# No Li and RDL/Metal 6 layer
# LEF technology file - generated from cadflow
# Creation date: Jul 5 2017
# 12-21-18 KKEL added OVERLAP layer; added EDGECAPACITANCE, 
#          CAPACITANCE CPERSQDIST, RESISTANCE RPERSQ,
#          DCCURRENTDENSITY AVERAGE, ACCURRENTDENSITY RMS 
#          for all relevant routing/cutlayers
# 04-01-19 KKEL removed off-grid offset value for METAL2
#          and simplified ACCURRENTDENSITY syntax to prevent 
#          RC Compiler parsing error

# Initilize top level parameters
VERSION 5.6 ;
BUSBITCHARS "[]" ;
DIVIDERCHAR "/" ;
UNITS
  TIME NANOSECONDS 1 ;
  CAPACITANCE PICOFARADS 1 ;
  RESISTANCE OHMS 1 ;
  DATABASE MICRONS 1000 ;
END UNITS
MANUFACTURINGGRID 0.005 ;

#### end of header section  #######

SITE unithd
    SYMMETRY y  ;
    CLASS CORE  ;
    SIZE  0.460 BY 2.720 ;
END unithd

SITE unit
    SYMMETRY y  ;
    CLASS CORE  ;
    SIZE  0.480 BY 3.330 ;
END unit

SITE unithv
    SYMMETRY y  ;
    CLASS CORE  ;
    SIZE  0.480 BY 4.070 ;
END unithv

######  Starting overlap layers #####
# ******** Layer OverlapCheck, type blockage, number 90 **************
LAYER OverlapCheck
  TYPE OVERLAP ;
END OverlapCheck

######  Starting routing layers - metal and via #####


# ******** Layer METAL1, type routing, number 36 **************
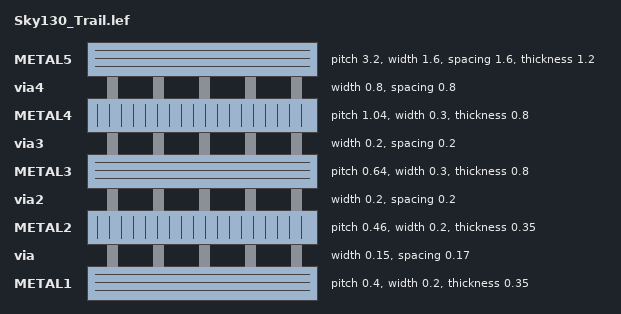
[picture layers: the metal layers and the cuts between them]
LAYER METAL1
  TYPE ROUTING ;
  DIRECTION HORIZONTAL ;
  #PITCH 0.340000 ;
  PITCH 0.40000 ;
  OFFSET 0.170000 ;
  MINENCLOSEDAREA 0.140000 ;
  MINWIDTH 0.140000 ;
  #WIDTH 0.140000 ;
  WIDTH 0.20000 ;
  AREA 0.083000 ;
  SPACINGTABLE
  PARALLELRUNLENGTH 0.000
    WIDTH 0.000 0.140000
    WIDTH 3.000000 0.280000
    ;
  THICKNESS 0.350000 ;
  EDGECAPACITANCE 1.79 ;
  CAPACITANCE CPERSQDIST 25800000 ;
  RESISTANCE RPERSQ 0.125 ;
  DCCURRENTDENSITY AVERAGE 2.8 ; # mA/um Iavg_max at Tj = 90oC
  ACCURRENTDENSITY RMS 6.1 ; # mA/um Irms_max at Tj = 90oC
  ANTENNADIFFSIDEAREARATIO PWL ( ( 0.000000 400.000000 ) ( 0.012500 400.000000 ) ( 0.022500 2609.000000 ) ( 22.500000 11600.000000 ) ) ;
END METAL1

# ******** Layer via, type routing, number 40 **************
LAYER via
  TYPE CUT ;
  SPACING 0.170000 ;
  WIDTH 0.150000 ;
  ANTENNADIFFAREARATIO PWL ( ( 0.000000 6.000000 ) ( 0.012500 6.000000 ) ( 0.022500 6.810000 ) ( 22.500000 816.000000 ) ) ;
  DCCURRENTDENSITY AVERAGE 0.29 ; # mA per via Iavg_max at Tj = 90oC
  ENCLOSURE BELOW 0.000000 0.000000 ;
  ENCLOSURE ABOVE 0.000000 0.000000 ;
END via

# ******** Layer METAL2, type routing, number 41 **************
LAYER METAL2
  TYPE ROUTING ;
  DIRECTION VERTICAL ;
  #PITCH 0.395000 ;
  PITCH 0.4600 ;
# Comment out: this value is off-grid!
# OFFSET 0.197500 ;
  MINENCLOSEDAREA 0.140000 ;
  MINWIDTH 0.140000 ;
  #WIDTH 0.140000 ;
  WIDTH 0.20000 ;
  AREA 0.067600 ;
  SPACINGTABLE
  PARALLELRUNLENGTH 0.000
    WIDTH 0.000 0.140000
    WIDTH 3.000000 0.280000
    ;
  THICKNESS 0.350000 ;
  EDGECAPACITANCE 1.22 ;
  CAPACITANCE CPERSQDIST 17500000 ;
  RESISTANCE RPERSQ 0.125 ;
  DCCURRENTDENSITY AVERAGE 2.8 ; # mA/um Iavg_max at Tj = 90oC
  ACCURRENTDENSITY RMS 6.1 ; # mA/um Irms_max at Tj = 90oC 
  ANTENNADIFFSIDEAREARATIO PWL ( ( 0.000000 400.000000 ) ( 0.012500 400.000000 ) ( 0.022500 2609.000000 ) ( 22.500000 11600.000000 ) ) ;
END METAL2

# ******** Layer via2, type routing, number 44 **************
LAYER via2
  TYPE CUT ;
  SPACING 0.200000 ;
  WIDTH 0.200000 ;
  ANTENNADIFFAREARATIO PWL ( ( 0.000000 6.000000 ) ( 0.012500 6.000000 ) ( 0.022500 6.810000 ) ( 22.500000 816.000000 ) ) ;
  DCCURRENTDENSITY AVERAGE 0.48 ; # mA per via Iavg_max at Tj = 90oC
  ENCLOSURE BELOW 0.000000 0.000000 ;
  ENCLOSURE ABOVE 0.000000 0.000000 ;
END via2

# ******** Layer METAL3, type routing, number 34 **************
LAYER METAL3
  TYPE ROUTING ;
  DIRECTION HORIZONTAL ;
  PITCH 0.640000 ;
  OFFSET 0.320000 ;
  MINWIDTH 0.300000 ;
  WIDTH 0.300000 ;
  AREA 0.240000 ;
  SPACINGTABLE
  PARALLELRUNLENGTH 0.000
    WIDTH 0.000 0.300000
    WIDTH 3.000000 0.400000
    ;
  THICKNESS 0.800000 ;
  EDGECAPACITANCE 1.86 ;
  CAPACITANCE CPERSQDIST 12600000 ;
  RESISTANCE RPERSQ 0.047 ;
  DCCURRENTDENSITY AVERAGE 6.8 ; # mA/um Iavg_max at Tj = 90oC
  ACCURRENTDENSITY RMS 14.9 ; # mA/um Irms_max at Tj = 90oC 
  ANTENNADIFFSIDEAREARATIO PWL ( ( 0.000000 400.000000 ) ( 0.012500 400.000000 ) ( 0.022500 2609.000000 ) ( 22.500000 11600.000000 ) ) ;
END METAL3

# ******** Layer via3, type routing, number 70 **************
LAYER via3
  TYPE CUT ;
  SPACING 0.200000 ;
  WIDTH 0.200000 ;
  ANTENNADIFFAREARATIO PWL ( ( 0.000000 6.000000 ) ( 0.012500 6.000000 ) ( 0.022500 6.810000 ) ( 22.500000 816.000000 ) ) ;
  DCCURRENTDENSITY AVERAGE 0.48 ; # mA per via Iavg_max at Tj = 90oC
  ENCLOSURE BELOW 0.000000 0.000000 ;
  ENCLOSURE ABOVE 0.000000 0.000000 ;
END via3

# ******** Layer METAL4, type routing, number 71 **************
LAYER METAL4
  TYPE ROUTING ;
  DIRECTION VERTICAL ;
  PITCH 1.040000 ;
  OFFSET 0.520000 ;
  MINWIDTH 0.300000 ;
  WIDTH 0.300000 ;
  AREA 0.240000 ;
  SPACINGTABLE
  PARALLELRUNLENGTH 0.000
    WIDTH 0.000 0.300000
    WIDTH 3.000000 0.400000
    ;
  THICKNESS 0.800000 ;
  EDGECAPACITANCE 1.29 ;
  CAPACITANCE CPERSQDIST 8670000 ;
  RESISTANCE RPERSQ 0.047 ;
  DCCURRENTDENSITY AVERAGE 6.8 ; # mA/um Iavg_max at Tj = 90oC
  ACCURRENTDENSITY RMS 14.9 ; # mA/um Irms_max at Tj = 90oC 
  ANTENNADIFFSIDEAREARATIO PWL ( ( 0.000000 400.000000 ) ( 0.012500 400.000000 ) ( 0.022500 2609.000000 ) ( 22.500000 11600.000000 ) ) ;
END METAL4

# ******** Layer via4, type routing, number 58 **************
LAYER via4
  TYPE CUT ;
  SPACING 0.800000 ;
  WIDTH 0.800000 ;
  ANTENNADIFFAREARATIO PWL ( ( 0.000000 6.000000 ) ( 0.012500 6.000000 ) ( 0.022500 6.810000 ) ( 22.500000 816.000000 ) ) ;
  DCCURRENTDENSITY AVERAGE 2.49 ; # mA per via Iavg_max at Tj = 90oC
  ENCLOSURE BELOW 0.000000 0.000000 ;
  ENCLOSURE ABOVE 0.000000 0.000000 ;
END via4

# ******** Layer METAL5, type routing, number 72 **************
LAYER METAL5
  TYPE ROUTING ;
  DIRECTION HORIZONTAL ;
  PITCH 3.200000 ;
  OFFSET 1.600000 ;
  MINWIDTH 1.600000 ;
  WIDTH 1.600000 ;
  AREA 2.560000 ;
  SPACING 1.600000 ;
  THICKNESS 1.200000 ;
  EDGECAPACITANCE 4.96 ;
  CAPACITANCE CPERSQDIST 6480000 ;
  RESISTANCE RPERSQ 0.047 ;
  DCCURRENTDENSITY AVERAGE 10.17 ; # mA/um Iavg_max at Tj = 90oC
  ACCURRENTDENSITY RMS 22.34 ; # mA/um Irms_max at Tj = 90oC 
  ANTENNADIFFSIDEAREARATIO PWL ( ( 0.000000 400.000000 ) ( 0.012500 400.000000 ) ( 0.022500 2609.000000 ) ( 22.500000 11600.000000 ) ) ;
END METAL5

######  completed routing layers - metal and via #####

### Routing via cells section   ###
# Plus via rule, metals are along the prefered direction

# Plus via rule, metals are along the prefered direction
VIA M1M2_PR DEFAULT
  LAYER via ;
  RECT -0.075000 -0.075000 0.075000 0.075000 ;
  LAYER METAL1 ;
  RECT -0.160000 -0.130000 0.160000 0.130000 ;
  LAYER METAL2 ;
  RECT -0.130000 -0.160000 0.130000 0.160000 ;
END M1M2_PR

VIARULE M1M2_PR GENERATE
  LAYER METAL1 ;
  ENCLOSURE 0.085000 0.055000 ;
  LAYER METAL2 ;
  ENCLOSURE 0.055000 0.085000 ;
  LAYER via ;
  RECT -0.075000 -0.075000 0.075000 0.075000 ;
  SPACING 0.320000 BY 0.320000 ;
END M1M2_PR

# Plus via rule, metals are along the non prefered direction
VIA M1M2_PR_R DEFAULT
  LAYER via ;
  RECT -0.075000 -0.075000 0.075000 0.075000 ;
  LAYER METAL1 ;
  RECT -0.130000 -0.160000 0.130000 0.160000 ;
  LAYER METAL2 ;
  RECT -0.160000 -0.130000 0.160000 0.130000 ;
END M1M2_PR_R

VIARULE M1M2_PR_R GENERATE
  LAYER METAL1 ;
  ENCLOSURE 0.055000 0.085000 ;
  LAYER METAL2 ;
  ENCLOSURE 0.085000 0.055000 ;
  LAYER via ;
  RECT -0.075000 -0.075000 0.075000 0.075000 ;
  SPACING 0.320000 BY 0.320000 ;
END M1M2_PR_R

# Minus via rule, lower layer metal is along prefered direction
VIA M1M2_PR_M DEFAULT
  LAYER via ;
  RECT -0.075000 -0.075000 0.075000 0.075000 ;
  LAYER METAL1 ;
  RECT -0.160000 -0.130000 0.160000 0.130000 ;
  LAYER METAL2 ;
  RECT -0.160000 -0.130000 0.160000 0.130000 ;
END M1M2_PR_M

VIARULE M1M2_PR_M GENERATE
  LAYER METAL1 ;
  ENCLOSURE 0.085000 0.055000 ;
  LAYER METAL2 ;
  ENCLOSURE 0.085000 0.055000 ;
  LAYER via ;
  RECT -0.075000 -0.075000 0.075000 0.075000 ;
  SPACING 0.320000 BY 0.320000 ;
END M1M2_PR_M

# Minus via rule, upper layer metal is along prefered direction
VIA M1M2_PR_MR DEFAULT
  LAYER via ;
  RECT -0.075000 -0.075000 0.075000 0.075000 ;
  LAYER METAL1 ;
  RECT -0.130000 -0.160000 0.130000 0.160000 ;
  LAYER METAL2 ;
  RECT -0.130000 -0.160000 0.130000 0.160000 ;
END M1M2_PR_MR

VIARULE M1M2_PR_MR GENERATE
  LAYER METAL1 ;
  ENCLOSURE 0.055000 0.085000 ;
  LAYER METAL2 ;
  ENCLOSURE 0.055000 0.085000 ;
  LAYER via ;
  RECT -0.075000 -0.075000 0.075000 0.075000 ;
  SPACING 0.320000 BY 0.320000 ;
END M1M2_PR_MR

# Centered via rule, we really do not want to use it
VIA M1M2_PR_C DEFAULT
  LAYER via ;
  RECT -0.075000 -0.075000 0.075000 0.075000 ;
  LAYER METAL1 ;
  RECT -0.160000 -0.160000 0.160000 0.160000 ;
  LAYER METAL2 ;
  RECT -0.160000 -0.160000 0.160000 0.160000 ;
END M1M2_PR_C

VIARULE M1M2_PR_C GENERATE
  LAYER METAL1 ;
  ENCLOSURE 0.085000 0.085000 ;
  LAYER METAL2 ;
  ENCLOSURE 0.085000 0.085000 ;
  LAYER via ;
  RECT -0.075000 -0.075000 0.075000 0.075000 ;
  SPACING 0.320000 BY 0.320000 ;
END M1M2_PR_C

# Plus via rule, metals are along the prefered direction
VIA M2M3_PR DEFAULT
  LAYER via2 ;
  RECT -0.100000 -0.100000 0.100000 0.100000 ;
  LAYER METAL2 ;
  RECT -0.140000 -0.185000 0.140000 0.185000 ;
  LAYER METAL3 ;
  RECT -0.165000 -0.165000 0.165000 0.165000 ;
END M2M3_PR

VIARULE M2M3_PR GENERATE
  LAYER METAL2 ;
  ENCLOSURE 0.040000 0.085000 ;
  LAYER METAL3 ;
  ENCLOSURE 0.065000 0.065000 ;
  LAYER via2 ;
  RECT -0.100000 -0.100000 0.100000 0.100000 ;
  SPACING 0.400000 BY 0.400000 ;
END M2M3_PR

# Plus via rule, metals are along the non prefered direction
VIA M2M3_PR_R DEFAULT
  LAYER via2 ;
  RECT -0.100000 -0.100000 0.100000 0.100000 ;
  LAYER METAL2 ;
  RECT -0.185000 -0.140000 0.185000 0.140000 ;
  LAYER METAL3 ;
  RECT -0.165000 -0.165000 0.165000 0.165000 ;
END M2M3_PR_R

VIARULE M2M3_PR_R GENERATE
  LAYER METAL2 ;
  ENCLOSURE 0.085000 0.040000 ;
  LAYER METAL3 ;
  ENCLOSURE 0.065000 0.065000 ;
  LAYER via2 ;
  RECT -0.100000 -0.100000 0.100000 0.100000 ;
  SPACING 0.400000 BY 0.400000 ;
END M2M3_PR_R

# Minus via rule, lower layer metal is along prefered direction
VIA M2M3_PR_M DEFAULT
  LAYER via2 ;
  RECT -0.100000 -0.100000 0.100000 0.100000 ;
  LAYER METAL2 ;
  RECT -0.140000 -0.185000 0.140000 0.185000 ;
  LAYER METAL3 ;
  RECT -0.165000 -0.165000 0.165000 0.165000 ;
END M2M3_PR_M

VIARULE M2M3_PR_M GENERATE
  LAYER METAL2 ;
  ENCLOSURE 0.040000 0.085000 ;
  LAYER METAL3 ;
  ENCLOSURE 0.065000 0.065000 ;
  LAYER via2 ;
  RECT -0.100000 -0.100000 0.100000 0.100000 ;
  SPACING 0.400000 BY 0.400000 ;
END M2M3_PR_M

# Minus via rule, upper layer metal is along prefered direction
VIA M2M3_PR_MR DEFAULT
  LAYER via2 ;
  RECT -0.100000 -0.100000 0.100000 0.100000 ;
  LAYER METAL2 ;
  RECT -0.185000 -0.140000 0.185000 0.140000 ;
  LAYER METAL3 ;
  RECT -0.165000 -0.165000 0.165000 0.165000 ;
END M2M3_PR_MR

VIARULE M2M3_PR_MR GENERATE
  LAYER METAL2 ;
  ENCLOSURE 0.085000 0.040000 ;
  LAYER METAL3 ;
  ENCLOSURE 0.065000 0.065000 ;
  LAYER via2 ;
  RECT -0.100000 -0.100000 0.100000 0.100000 ;
  SPACING 0.400000 BY 0.400000 ;
END M2M3_PR_MR

# Centered via rule, we really do not want to use it
VIA M2M3_PR_C DEFAULT
  LAYER via2 ;
  RECT -0.100000 -0.100000 0.100000 0.100000 ;
  LAYER METAL2 ;
  RECT -0.185000 -0.185000 0.185000 0.185000 ;
  LAYER METAL3 ;
  RECT -0.165000 -0.165000 0.165000 0.165000 ;
END M2M3_PR_C

VIARULE M2M3_PR_C GENERATE
  LAYER METAL2 ;
  ENCLOSURE 0.085000 0.085000 ;
  LAYER METAL3 ;
  ENCLOSURE 0.065000 0.065000 ;
  LAYER via2 ;
  RECT -0.100000 -0.100000 0.100000 0.100000 ;
  SPACING 0.400000 BY 0.400000 ;
END M2M3_PR_C

# Plus via rule, metals are along the prefered direction
VIA M3M4_PR DEFAULT
  LAYER via3 ;
  RECT -0.100000 -0.100000 0.100000 0.100000 ;
  LAYER METAL3 ;
  RECT -0.190000 -0.160000 0.190000 0.160000 ;
  LAYER METAL4 ;
  RECT -0.165000 -0.165000 0.165000 0.165000 ;
END M3M4_PR

VIARULE M3M4_PR GENERATE
  LAYER METAL3 ;
  ENCLOSURE 0.090000 0.060000 ;
  LAYER METAL4 ;
  ENCLOSURE 0.065000 0.065000 ;
  LAYER via3 ;
  RECT -0.100000 -0.100000 0.100000 0.100000 ;
  SPACING 0.400000 BY 0.400000 ;
END M3M4_PR

# Plus via rule, metals are along the non prefered direction
VIA M3M4_PR_R DEFAULT
  LAYER via3 ;
  RECT -0.100000 -0.100000 0.100000 0.100000 ;
  LAYER METAL3 ;
  RECT -0.160000 -0.190000 0.160000 0.190000 ;
  LAYER METAL4 ;
  RECT -0.165000 -0.165000 0.165000 0.165000 ;
END M3M4_PR_R

VIARULE M3M4_PR_R GENERATE
  LAYER METAL3 ;
  ENCLOSURE 0.060000 0.090000 ;
  LAYER METAL4 ;
  ENCLOSURE 0.065000 0.065000 ;
  LAYER via3 ;
  RECT -0.100000 -0.100000 0.100000 0.100000 ;
  SPACING 0.400000 BY 0.400000 ;
END M3M4_PR_R

# Minus via rule, lower layer metal is along prefered direction
VIA M3M4_PR_M DEFAULT
  LAYER via3 ;
  RECT -0.100000 -0.100000 0.100000 0.100000 ;
  LAYER METAL3 ;
  RECT -0.190000 -0.160000 0.190000 0.160000 ;
  LAYER METAL4 ;
  RECT -0.165000 -0.165000 0.165000 0.165000 ;
END M3M4_PR_M

VIARULE M3M4_PR_M GENERATE
  LAYER METAL3 ;
  ENCLOSURE 0.090000 0.060000 ;
  LAYER METAL4 ;
  ENCLOSURE 0.065000 0.065000 ;
  LAYER via3 ;
  RECT -0.100000 -0.100000 0.100000 0.100000 ;
  SPACING 0.400000 BY 0.400000 ;
END M3M4_PR_M

# Minus via rule, upper layer metal is along prefered direction
VIA M3M4_PR_MR DEFAULT
  LAYER via3 ;
  RECT -0.100000 -0.100000 0.100000 0.100000 ;
  LAYER METAL3 ;
  RECT -0.160000 -0.190000 0.160000 0.190000 ;
  LAYER METAL4 ;
  RECT -0.165000 -0.165000 0.165000 0.165000 ;
END M3M4_PR_MR

VIARULE M3M4_PR_MR GENERATE
  LAYER METAL3 ;
  ENCLOSURE 0.060000 0.090000 ;
  LAYER METAL4 ;
  ENCLOSURE 0.065000 0.065000 ;
  LAYER via3 ;
  RECT -0.100000 -0.100000 0.100000 0.100000 ;
  SPACING 0.400000 BY 0.400000 ;
END M3M4_PR_MR

# Centered via rule, we really do not want to use it
VIA M3M4_PR_C DEFAULT
  LAYER via3 ;
  RECT -0.100000 -0.100000 0.100000 0.100000 ;
  LAYER METAL3 ;
  RECT -0.190000 -0.190000 0.190000 0.190000 ;
  LAYER METAL4 ;
  RECT -0.165000 -0.165000 0.165000 0.165000 ;
END M3M4_PR_C

VIARULE M3M4_PR_C GENERATE
  LAYER METAL3 ;
  ENCLOSURE 0.090000 0.090000 ;
  LAYER METAL4 ;
  ENCLOSURE 0.065000 0.065000 ;
  LAYER via3 ;
  RECT -0.100000 -0.100000 0.100000 0.100000 ;
  SPACING 0.400000 BY 0.400000 ;
END M3M4_PR_C

# Plus via rule, metals are along the prefered direction
VIA M4M5_PR DEFAULT
  LAYER via4 ;
  RECT -0.400000 -0.400000 0.400000 0.400000 ;
  LAYER METAL4 ;
  RECT -0.590000 -0.590000 0.590000 0.590000 ;
  LAYER METAL5 ;
  RECT -0.710000 -0.710000 0.710000 0.710000 ;
END M4M5_PR

VIARULE M4M5_PR GENERATE
  LAYER METAL4 ;
  ENCLOSURE 0.190000 0.190000 ;
  LAYER METAL5 ;
  ENCLOSURE 0.310000 0.310000 ;
  LAYER via4 ;
  RECT -0.400000 -0.400000 0.400000 0.400000 ;
  SPACING 1.600000 BY 1.600000 ;
END M4M5_PR

# Plus via rule, metals are along the non prefered direction
VIA M4M5_PR_R DEFAULT
  LAYER via4 ;
  RECT -0.400000 -0.400000 0.400000 0.400000 ;
  LAYER METAL4 ;
  RECT -0.590000 -0.590000 0.590000 0.590000 ;
  LAYER METAL5 ;
  RECT -0.710000 -0.710000 0.710000 0.710000 ;
END M4M5_PR_R

VIARULE M4M5_PR_R GENERATE
  LAYER METAL4 ;
  ENCLOSURE 0.190000 0.190000 ;
  LAYER METAL5 ;
  ENCLOSURE 0.310000 0.310000 ;
  LAYER via4 ;
  RECT -0.400000 -0.400000 0.400000 0.400000 ;
  SPACING 1.600000 BY 1.600000 ;
END M4M5_PR_R

# Minus via rule, lower layer metal is along prefered direction
VIA M4M5_PR_M DEFAULT
  LAYER via4 ;
  RECT -0.400000 -0.400000 0.400000 0.400000 ;
  LAYER METAL4 ;
  RECT -0.590000 -0.590000 0.590000 0.590000 ;
  LAYER METAL5 ;
  RECT -0.710000 -0.710000 0.710000 0.710000 ;
END M4M5_PR_M

VIARULE M4M5_PR_M GENERATE
  LAYER METAL4 ;
  ENCLOSURE 0.190000 0.190000 ;
  LAYER METAL5 ;
  ENCLOSURE 0.310000 0.310000 ;
  LAYER via4 ;
  RECT -0.400000 -0.400000 0.400000 0.400000 ;
  SPACING 1.600000 BY 1.600000 ;
END M4M5_PR_M

# Minus via rule, upper layer metal is along prefered direction
VIA M4M5_PR_MR DEFAULT
  LAYER via4 ;
  RECT -0.400000 -0.400000 0.400000 0.400000 ;
  LAYER METAL4 ;
  RECT -0.590000 -0.590000 0.590000 0.590000 ;
  LAYER METAL5 ;
  RECT -0.710000 -0.710000 0.710000 0.710000 ;
END M4M5_PR_MR

VIARULE M4M5_PR_MR GENERATE
  LAYER METAL4 ;
  ENCLOSURE 0.190000 0.190000 ;
  LAYER METAL5 ;
  ENCLOSURE 0.310000 0.310000 ;
  LAYER via4 ;
  RECT -0.400000 -0.400000 0.400000 0.400000 ;
  SPACING 1.600000 BY 1.600000 ;
END M4M5_PR_MR

# Centered via rule, we really do not want to use it
VIA M4M5_PR_C DEFAULT
  LAYER via4 ;
  RECT -0.400000 -0.400000 0.400000 0.400000 ;
  LAYER METAL4 ;
  RECT -0.590000 -0.590000 0.590000 0.590000 ;
  LAYER METAL5 ;
  RECT -0.710000 -0.710000 0.710000 0.710000 ;
END M4M5_PR_C

VIARULE M4M5_PR_C GENERATE
  LAYER METAL4 ;
  ENCLOSURE 0.190000 0.190000 ;
  LAYER METAL5 ;
  ENCLOSURE 0.310000 0.310000 ;
  LAYER via4 ;
  RECT -0.400000 -0.400000 0.400000 0.400000 ;
  SPACING 1.600000 BY 1.600000 ;
END M4M5_PR_C


###  end of single via cells   ###

#END LIBRARY

# Autogenerated


MACRO IndirectVMM_4x2
  PIN Vd_P_e[3]
    DIRECTION INOUT ;
    USE SIGNAL ;
    PORT
      LAYER METAL2 ;
        RECT 16.85 0.84 17.11 1.3 ;
    END
  END Vd_P_e[3]
  PIN Vd_R_e[3]
    DIRECTION INOUT ;
    USE SIGNAL ;
    PORT
      LAYER METAL2 ;
        RECT 16.85 1.53 17.11 1.99 ;
    END
  END Vd_R_e[3]
  PIN Vd_R_e[2]
    DIRECTION INOUT ;
    USE SIGNAL ;
    PORT
      LAYER METAL2 ;
        RECT 16.85 2.22 17.11 2.68 ;
    END
  END Vd_R_e[2]
  PIN Vd_P_e[2]
    DIRECTION INOUT ;
    USE SIGNAL ;
    PORT
      LAYER METAL2 ;
        RECT 16.85 2.91 17.11 3.37 ;
    END
  END Vd_P_e[2]
  PIN Vd_P_e[1]
    DIRECTION INOUT ;
    USE SIGNAL ;
    PORT
      LAYER METAL2 ;
        RECT 16.85 3.6 17.11 4.06 ;
    END
  END Vd_P_e[1]
  PIN Vd_R_e[1]
    DIRECTION INOUT ;
    USE SIGNAL ;
    PORT
      LAYER METAL2 ;
        RECT 16.85 4.29 17.11 4.75 ;
    END
  END Vd_R_e[1]
  PIN Vd_R_e[0]
    DIRECTION INOUT ;
    USE SIGNAL ;
    PORT
      LAYER METAL2 ;
        RECT 16.85 4.98 17.11 5.44 ;
    END
  END Vd_R_e[0]
  PIN Vd_P_e[0]
    DIRECTION INOUT ;
    USE SIGNAL ;
    PORT
      LAYER METAL2 ;
        RECT 16.85 5.67 17.11 6.13 ;
    END
  END Vd_P_e[0]
  PIN Vd_P_w[3]
    DIRECTION INOUT ;
    USE SIGNAL ;
    PORT
      LAYER METAL2 ;
        RECT 0.0 0.84 0.23 1.3 ;
    END
  END Vd_P_w[3]
  PIN Vd_R_w[3]
    DIRECTION INOUT ;
    USE SIGNAL ;
    PORT
      LAYER METAL2 ;
        RECT 0.0 1.53 0.26 1.99 ;
    END
  END Vd_R_w[3]
  PIN Vd_R_w[2]
    DIRECTION INOUT ;
    USE SIGNAL ;
    PORT
      LAYER METAL2 ;
        RECT 0.0 2.22 0.26 2.68 ;
    END
  END Vd_R_w[2]
  PIN Vd_P_w[2]
    DIRECTION INOUT ;
    USE SIGNAL ;
    PORT
      LAYER METAL2 ;
        RECT 0.0 2.91 0.26 3.37 ;
    END
  END Vd_P_w[2]
  PIN Vd_P_w[1]
    DIRECTION INOUT ;
    USE SIGNAL ;
    PORT
      LAYER METAL2 ;
        RECT 0.0 3.6 0.26 4.06 ;
    END
  END Vd_P_w[1]
  PIN Vd_R_w[1]
    DIRECTION INOUT ;
    USE SIGNAL ;
    PORT
      LAYER METAL2 ;
        RECT 0.0 4.29 0.26 4.75 ;
    END
  END Vd_R_w[1]
  PIN Vd_R_w[0]
    DIRECTION INOUT ;
    USE SIGNAL ;
    PORT
      LAYER METAL2 ;
        RECT 0.0 4.98 0.26 5.44 ;
    END
  END Vd_R_w[0]
  PIN Vd_P_w[0]
    DIRECTION INOUT ;
    USE SIGNAL ;
    PORT
      LAYER METAL2 ;
        RECT 0.0 5.67 0.26 6.13 ;
    END
  END Vd_P_w[0]
  PIN Vsel_n[0]
    DIRECTION INOUT ;
    USE SIGNAL ;
    PORT
      LAYER METAL1 ;
        RECT 0.35 6.25 0.75 6.5 ;
    END
  END Vsel_n[0]
  PIN Vs_n[0]
    DIRECTION INOUT ;
    USE SIGNAL ;
    PORT
      LAYER METAL1 ;
        RECT 0.95 6.25 1.35 6.5 ;
    END
  END Vs_n[0]
  PIN VINJ_n[0]
    DIRECTION INOUT ;
    USE SIGNAL ;
    PORT
      LAYER METAL1 ;
        RECT 1.55 6.25 1.95 6.5 ;
    END
  END VINJ_n[0]
  PIN GND_n[0]
    DIRECTION INOUT ;
    USE SIGNAL ;
    PORT
      LAYER METAL1 ;
        RECT 3.13 6.25 3.53 6.5 ;
    END
  END GND_n[0]
  PIN GND_n[1]
    DIRECTION INOUT ;
    USE SIGNAL ;
    PORT
      LAYER METAL1 ;
        RECT 5.88 6.25 6.28 6.5 ;
    END
  END GND_n[1]
  PIN GND_n[2]
    DIRECTION INOUT ;
    USE SIGNAL ;
    PORT
      LAYER METAL1 ;
        RECT 10.83 6.25 11.23 6.5 ;
    END
  END GND_n[2]
  PIN GND_n[3]
    DIRECTION INOUT ;
    USE SIGNAL ;
    PORT
      LAYER METAL1 ;
        RECT 13.58 6.25 13.98 6.5 ;
    END
  END GND_n[3]
  PIN Vg_n[0]
    DIRECTION INOUT ;
    USE SIGNAL ;
    PORT
      LAYER METAL1 ;
        RECT 4.46 6.25 4.86 6.5 ;
    END
  END Vg_n[0]
  PIN VTUN_n[0]
    DIRECTION INOUT ;
    USE SIGNAL ;
    PORT
      LAYER METAL1 ;
        RECT 7.4 6.25 7.8 6.5 ;
    END
  END VTUN_n[0]
  PIN VTUN_n[1]
    DIRECTION INOUT ;
    USE SIGNAL ;
    PORT
      LAYER METAL1 ;
        RECT 9.31 6.25 9.71 6.5 ;
    END
  END VTUN_n[1]
  PIN Vg_n[1]
    DIRECTION INOUT ;
    USE SIGNAL ;
    PORT
      LAYER METAL1 ;
        RECT 12.25 6.25 12.65 6.5 ;
    END
  END Vg_n[1]
  PIN VINJ_n[1]
    DIRECTION INOUT ;
    USE SIGNAL ;
    PORT
      LAYER METAL1 ;
        RECT 15.16 6.25 15.56 6.5 ;
    END
  END VINJ_n[1]
  PIN Vs_n[1]
    DIRECTION INOUT ;
    USE SIGNAL ;
    PORT
      LAYER METAL1 ;
        RECT 15.76 6.25 16.16 6.5 ;
    END
  END Vs_n[1]
  PIN Vsel_n[1]
    DIRECTION INOUT ;
    USE SIGNAL ;
    PORT
      LAYER METAL1 ;
        RECT 16.36 6.25 16.76 6.5 ;
    END
  END Vsel_n[1]
  PIN Vsel_s[0]
    DIRECTION INOUT ;
    USE SIGNAL ;
    PORT
      LAYER METAL1 ;
        RECT 0.35 0.0 0.75 0.25 ;
    END
  END Vsel_s[0]
  PIN Vs_s[0]
    DIRECTION INOUT ;
    USE SIGNAL ;
    PORT
      LAYER METAL1 ;
        RECT 0.95 0.0 1.35 0.25 ;
    END
  END Vs_s[0]
  PIN VINJ_s[0]
    DIRECTION INOUT ;
    USE SIGNAL ;
    PORT
      LAYER METAL1 ;
        RECT 1.55 0.0 1.95 0.25 ;
    END
  END VINJ_s[0]
  PIN GND_s[0]
    DIRECTION INOUT ;
    USE SIGNAL ;
    PORT
      LAYER METAL1 ;
        RECT 3.13 0.0 3.53 0.25 ;
    END
  END GND_s[0]
  PIN GND_s[1]
    DIRECTION INOUT ;
    USE SIGNAL ;
    PORT
      LAYER METAL1 ;
        RECT 5.88 0.0 6.28 0.25 ;
    END
  END GND_s[1]
  PIN GND_s[2]
    DIRECTION INOUT ;
    USE SIGNAL ;
    PORT
      LAYER METAL1 ;
        RECT 13.58 0.0 13.98 0.25 ;
    END
  END GND_s[2]
  PIN Vg_s[0]
    DIRECTION INOUT ;
    USE SIGNAL ;
    PORT
      LAYER METAL1 ;
        RECT 4.46 0.0 4.86 0.25 ;
    END
  END Vg_s[0]
  PIN Vg_s[1]
    DIRECTION INOUT ;
    USE SIGNAL ;
    PORT
      LAYER METAL1 ;
        RECT 12.25 0.0 12.65 0.25 ;
    END
  END Vg_s[1]
  PIN VINJ_s[1]
    DIRECTION INOUT ;
    USE SIGNAL ;
    PORT
      LAYER METAL1 ;
        RECT 15.16 0.0 15.56 0.25 ;
    END
  END VINJ_s[1]
  PIN Vs_s[1]
    DIRECTION INOUT ;
    USE SIGNAL ;
    PORT
      LAYER METAL1 ;
        RECT 15.76 0.0 16.16 0.25 ;
    END
  END Vs_s[1]
  PIN Vsel_s[1]
    DIRECTION INOUT ;
    USE SIGNAL ;
    PORT
      LAYER METAL1 ;
        RECT 16.36 0.0 16.76 0.25 ;
    END
  END Vsel_s[1]
  PIN VTUN_s[0]
    DIRECTION INOUT ;
    USE SIGNAL ;
    PORT
      LAYER METAL1 ;
        RECT 7.4 0.0 7.8 0.25 ;
    END
  END VTUN_s[0]
  PIN VTUN_s[1]
    DIRECTION INOUT ;
    USE SIGNAL ;
    PORT
      LAYER METAL1 ;
        RECT 9.31 0.0 9.71 0.25 ;
    END
  END VTUN_s[1]
END IndirectVMM_4x2

MACRO tile_analog_frame
  PIN n_Vg[0]
    DIRECTION INOUT ;
    USE SIGNAL ;
    PORT
      LAYER METAL3 ;
        RECT 4.16 106.8 5.76 110.0 ;
    END
  END n_Vg[0]
  PIN n_Vg[1]
    DIRECTION INOUT ;
    USE SIGNAL ;
    PORT
      LAYER METAL3 ;
        RECT 9.12 106.8 10.72 110.0 ;
    END
  END n_Vg[1]
  PIN n_Vg[2]
    DIRECTION INOUT ;
    USE SIGNAL ;
    PORT
      LAYER METAL3 ;
        RECT 14.08 106.8 15.68 110.0 ;
    END
  END n_Vg[2]
  PIN n_Vg[3]
    DIRECTION INOUT ;
    USE SIGNAL ;
    PORT
      LAYER METAL3 ;
        RECT 19.04 106.8 20.64 110.0 ;
    END
  END n_Vg[3]
  PIN n_Vg[4]
    DIRECTION INOUT ;
    USE SIGNAL ;
    PORT
      LAYER METAL3 ;
        RECT 24.0 106.8 25.6 110.0 ;
    END
  END n_Vg[4]
  PIN n_Vg[5]
    DIRECTION INOUT ;
    USE SIGNAL ;
    PORT
      LAYER METAL3 ;
        RECT 28.96 106.8 30.56 110.0 ;
    END
  END n_Vg[5]
  PIN n_Vg[6]
    DIRECTION INOUT ;
    USE SIGNAL ;
    PORT
      LAYER METAL3 ;
        RECT 33.92 106.8 35.52 110.0 ;
    END
  END n_Vg[6]
  PIN n_Vg[7]
    DIRECTION INOUT ;
    USE SIGNAL ;
    PORT
      LAYER METAL3 ;
        RECT 38.88 106.8 40.48 110.0 ;
    END
  END n_Vg[7]
  PIN n_Vg[8]
    DIRECTION INOUT ;
    USE SIGNAL ;
    PORT
      LAYER METAL3 ;
        RECT 43.84 106.8 45.44 110.0 ;
    END
  END n_Vg[8]
  PIN n_Vsel[0]
    DIRECTION INOUT ;
    USE SIGNAL ;
    PORT
      LAYER METAL3 ;
        RECT 48.8 106.8 50.4 110.0 ;
    END
  END n_Vsel[0]
  PIN n_Vsel[1]
    DIRECTION INOUT ;
    USE SIGNAL ;
    PORT
      LAYER METAL3 ;
        RECT 53.76 106.8 55.36 110.0 ;
    END
  END n_Vsel[1]
  PIN n_Vsel[2]
    DIRECTION INOUT ;
    USE SIGNAL ;
    PORT
      LAYER METAL3 ;
        RECT 58.72 106.8 60.32 110.0 ;
    END
  END n_Vsel[2]
  PIN n_Vsel[3]
    DIRECTION INOUT ;
    USE SIGNAL ;
    PORT
      LAYER METAL3 ;
        RECT 63.68 106.8 65.28 110.0 ;
    END
  END n_Vsel[3]
  PIN n_Vsel[4]
    DIRECTION INOUT ;
    USE SIGNAL ;
    PORT
      LAYER METAL3 ;
        RECT 68.64 106.8 70.24 110.0 ;
    END
  END n_Vsel[4]
  PIN n_Vsel[5]
    DIRECTION INOUT ;
    USE SIGNAL ;
    PORT
      LAYER METAL3 ;
        RECT 73.6 106.8 75.2 110.0 ;
    END
  END n_Vsel[5]
  PIN n_Vsel[6]
    DIRECTION INOUT ;
    USE SIGNAL ;
    PORT
      LAYER METAL3 ;
        RECT 78.56 106.8 80.16 110.0 ;
    END
  END n_Vsel[6]
  PIN n_Vsel[7]
    DIRECTION INOUT ;
    USE SIGNAL ;
    PORT
      LAYER METAL3 ;
        RECT 83.52 106.8 85.12 110.0 ;
    END
  END n_Vsel[7]
  PIN n_Vsel[8]
    DIRECTION INOUT ;
    USE SIGNAL ;
    PORT
      LAYER METAL3 ;
        RECT 88.48 106.8 90.08 110.0 ;
    END
  END n_Vsel[8]
  PIN n_Output[0]
    DIRECTION INOUT ;
    USE SIGNAL ;
    PORT
      LAYER METAL3 ;
        RECT 93.44 106.8 95.04 110.0 ;
    END
  END n_Output[0]
  PIN n_Output[1]
    DIRECTION INOUT ;
    USE SIGNAL ;
    PORT
      LAYER METAL3 ;
        RECT 98.4 106.8 100.0 110.0 ;
    END
  END n_Output[1]
  PIN n_Output[2]
    DIRECTION INOUT ;
    USE SIGNAL ;
    PORT
      LAYER METAL3 ;
        RECT 103.36 106.8 104.96 110.0 ;
    END
  END n_Output[2]
  PIN n_Output[3]
    DIRECTION INOUT ;
    USE SIGNAL ;
    PORT
      LAYER METAL3 ;
        RECT 108.32 106.8 109.92 110.0 ;
    END
  END n_Output[3]
  PIN n_Output[4]
    DIRECTION INOUT ;
    USE SIGNAL ;
    PORT
      LAYER METAL3 ;
        RECT 113.28 106.8 114.88 110.0 ;
    END
  END n_Output[4]
  PIN n_Output[5]
    DIRECTION INOUT ;
    USE SIGNAL ;
    PORT
      LAYER METAL3 ;
        RECT 118.24 106.8 119.84 110.0 ;
    END
  END n_Output[5]
  PIN n_Output[6]
    DIRECTION INOUT ;
    USE SIGNAL ;
    PORT
      LAYER METAL3 ;
        RECT 123.2 106.8 124.8 110.0 ;
    END
  END n_Output[6]
  PIN n_Output[7]
    DIRECTION INOUT ;
    USE SIGNAL ;
    PORT
      LAYER METAL3 ;
        RECT 128.16 106.8 129.76 110.0 ;
    END
  END n_Output[7]
  PIN w_Vd_P[0]
    DIRECTION INOUT ;
    USE SIGNAL ;
    PORT
      LAYER METAL3 ;
        RECT 0.0 103.44 3.2 105.04 ;
    END
  END w_Vd_P[0]
  PIN w_Vd_P[1]
    DIRECTION INOUT ;
    USE SIGNAL ;
    PORT
      LAYER METAL3 ;
        RECT 0.0 98.48 3.2 100.08 ;
    END
  END w_Vd_P[1]
  PIN w_Vd_P[2]
    DIRECTION INOUT ;
    USE SIGNAL ;
    PORT
      LAYER METAL3 ;
        RECT 0.0 93.52 3.2 95.12 ;
    END
  END w_Vd_P[2]
  PIN w_Vd_P[3]
    DIRECTION INOUT ;
    USE SIGNAL ;
    PORT
      LAYER METAL3 ;
        RECT 0.0 88.56 3.2 90.16 ;
    END
  END w_Vd_P[3]
  PIN w_Vd_P[4]
    DIRECTION INOUT ;
    USE SIGNAL ;
    PORT
      LAYER METAL3 ;
        RECT 0.0 83.6 3.2 85.2 ;
    END
  END w_Vd_P[4]
  PIN w_Vd_P[5]
    DIRECTION INOUT ;
    USE SIGNAL ;
    PORT
      LAYER METAL3 ;
        RECT 0.0 78.64 3.2 80.24 ;
    END
  END w_Vd_P[5]
  PIN w_Vd_P[6]
    DIRECTION INOUT ;
    USE SIGNAL ;
    PORT
      LAYER METAL3 ;
        RECT 0.0 73.68 3.2 75.28 ;
    END
  END w_Vd_P[6]
  PIN w_Vd_P[7]
    DIRECTION INOUT ;
    USE SIGNAL ;
    PORT
      LAYER METAL3 ;
        RECT 0.0 68.72 3.2 70.32 ;
    END
  END w_Vd_P[7]
  PIN w_Vd_P[8]
    DIRECTION INOUT ;
    USE SIGNAL ;
    PORT
      LAYER METAL3 ;
        RECT 0.0 63.76 3.2 65.36 ;
    END
  END w_Vd_P[8]
  PIN w_Vd_P[9]
    DIRECTION INOUT ;
    USE SIGNAL ;
    PORT
      LAYER METAL3 ;
        RECT 0.0 58.8 3.2 60.4 ;
    END
  END w_Vd_P[9]
  PIN w_Vd_P[10]
    DIRECTION INOUT ;
    USE SIGNAL ;
    PORT
      LAYER METAL3 ;
        RECT 0.0 53.84 3.2 55.44 ;
    END
  END w_Vd_P[10]
  PIN w_Vd_P[11]
    DIRECTION INOUT ;
    USE SIGNAL ;
    PORT
      LAYER METAL3 ;
        RECT 0.0 48.88 3.2 50.48 ;
    END
  END w_Vd_P[11]
  PIN w_Vd_P[12]
    DIRECTION INOUT ;
    USE SIGNAL ;
    PORT
      LAYER METAL3 ;
        RECT 0.0 43.92 3.2 45.52 ;
    END
  END w_Vd_P[12]
  PIN w_Vd_P[13]
    DIRECTION INOUT ;
    USE SIGNAL ;
    PORT
      LAYER METAL3 ;
        RECT 0.0 38.96 3.2 40.56 ;
    END
  END w_Vd_P[13]
  PIN w_Vd_P[14]
    DIRECTION INOUT ;
    USE SIGNAL ;
    PORT
      LAYER METAL3 ;
        RECT 0.0 34.0 3.2 35.6 ;
    END
  END w_Vd_P[14]
  PIN w_Vd_P[15]
    DIRECTION INOUT ;
    USE SIGNAL ;
    PORT
      LAYER METAL3 ;
        RECT 0.0 29.04 3.2 30.64 ;
    END
  END w_Vd_P[15]
END tile_analog_frame

MACRO TA_FGbias_1x2
  PIN Vin_P_w[0]
    DIRECTION INOUT ;
    USE SIGNAL ;
    PORT
      LAYER METAL2 ;
        RECT 0.0 0.26 0.26 0.72 ;
    END
  END Vin_P_w[0]
  PIN Vin_M_w[1]
    DIRECTION INOUT ;
    USE SIGNAL ;
    PORT
      LAYER METAL2 ;
        RECT 0.0 1.01 0.26 1.47 ;
    END
  END Vin_M_w[1]
  PIN Vd_P_w[0]
    DIRECTION INOUT ;
    USE SIGNAL ;
    PORT
      LAYER METAL2 ;
        RECT 0.0 5.14 0.26 5.6 ;
    END
  END Vd_P_w[0]
  PIN Vin_P_w[1]
    DIRECTION INOUT ;
    USE SIGNAL ;
    PORT
      LAYER METAL2 ;
        RECT 0.0 5.83 0.26 6.29 ;
    END
  END Vin_P_w[1]
  PIN GND_w
    DIRECTION INOUT ;
    USE SIGNAL ;
    PORT
      LAYER METAL2 ;
        RECT 0.0 3.49 0.26 3.95 ;
    END
  END GND_w
  PIN OUTPUT_e[0]
    DIRECTION INOUT ;
    USE SIGNAL ;
    PORT
      LAYER METAL2 ;
        RECT 27.204 3.35 27.6 3.97 ;
    END
  END OUTPUT_e[0]
  PIN Vd_P_w[1]
    DIRECTION INOUT ;
    USE SIGNAL ;
    PORT
      LAYER METAL2 ;
        RECT 0.0 2.8 0.26 3.26 ;
    END
  END Vd_P_w[1]
  PIN Vin_M_w[0]
    DIRECTION INOUT ;
    USE SIGNAL ;
    PORT
      LAYER METAL2 ;
        RECT 0.0 4.45 0.26 4.91 ;
    END
  END Vin_M_w[0]
  PIN OUTPUT_e[1]
    DIRECTION INOUT ;
    USE SIGNAL ;
    PORT
      LAYER METAL2 ;
        RECT 27.34 2.52 27.6 2.98 ;
    END
  END OUTPUT_e[1]
  PIN GND_s[0]
    DIRECTION INOUT ;
    USE SIGNAL ;
    PORT
      LAYER METAL1 ;
        RECT 2.24 0.0 2.64 0.25 ;
    END
  END GND_s[0]
  PIN GND_n[0]
    DIRECTION INOUT ;
    USE SIGNAL ;
    PORT
      LAYER METAL1 ;
        RECT 2.24 6.25 2.64 6.5 ;
    END
  END GND_n[0]
  PIN Vg_n
    DIRECTION INOUT ;
    USE SIGNAL ;
    PORT
      LAYER METAL1 ;
        RECT 3.45 6.25 3.85 6.5 ;
    END
  END Vg_n
  PIN Vg_s
    DIRECTION INOUT ;
    USE SIGNAL ;
    PORT
      LAYER METAL1 ;
        RECT 3.45 0.0 3.85 0.25 ;
    END
  END Vg_s
  PIN Vsel_n
    DIRECTION INOUT ;
    USE SIGNAL ;
    PORT
      LAYER METAL1 ;
        RECT 8.62 6.25 9.02 6.5 ;
    END
  END Vsel_n
  PIN Vsel_s
    DIRECTION INOUT ;
    USE SIGNAL ;
    PORT
      LAYER METAL1 ;
        RECT 8.62 0.0 9.02 0.25 ;
    END
  END Vsel_s
  PIN AVDD_s[0]
    DIRECTION INOUT ;
    USE SIGNAL ;
    PORT
      LAYER METAL1 ;
        RECT 10.59 0.0 11.03 0.25 ;
    END
  END AVDD_s[0]
  PIN AVDD_n[0]
    DIRECTION INOUT ;
    USE SIGNAL ;
    PORT
      LAYER METAL1 ;
        RECT 10.59 6.25 11.03 6.5 ;
    END
  END AVDD_n[0]
  PIN GND_s[1]
    DIRECTION INOUT ;
    USE SIGNAL ;
    PORT
      LAYER METAL1 ;
        RECT 22.2 0.0 22.64 0.25 ;
    END
  END GND_s[1]
  PIN GND_n[1]
    DIRECTION INOUT ;
    USE SIGNAL ;
    PORT
      LAYER METAL1 ;
        RECT 22.2 6.25 22.64 6.5 ;
    END
  END GND_n[1]
  PIN AVDD_s[1]
    DIRECTION INOUT ;
    USE SIGNAL ;
    PORT
      LAYER METAL1 ;
        RECT 25.25 0.0 25.69 0.25 ;
    END
  END AVDD_s[1]
  PIN AVDD_n[1]
    DIRECTION INOUT ;
    USE SIGNAL ;
    PORT
      LAYER METAL1 ;
        RECT 25.25 6.25 25.69 6.5 ;
    END
  END AVDD_n[1]
  PIN VTUN_s
    DIRECTION INOUT ;
    USE SIGNAL ;
    PORT
      LAYER METAL1 ;
        RECT 0.35 0.0 0.75 0.25 ;
    END
  END VTUN_s
  PIN VINJ_s
    DIRECTION INOUT ;
    USE SIGNAL ;
    PORT
      LAYER METAL1 ;
        RECT 7.78 0.0 8.18 0.25 ;
    END
  END VINJ_s
  PIN VINJ_n
    DIRECTION INOUT ;
    USE SIGNAL ;
    PORT
      LAYER METAL1 ;
        RECT 7.78 6.25 8.18 6.5 ;
    END
  END VINJ_n
  PIN VTUN_n
    DIRECTION INOUT ;
    USE SIGNAL ;
    PORT
      LAYER METAL1 ;
        RECT 0.35 6.25 0.75 6.5 ;
    END
  END VTUN_n
END TA_FGbias_1x2

END LIBRARY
